VERSION 5.8 ;
BUSBITCHARS "[]" ;
DIVIDERCHAR "/" ;
UNITS
 DATABASE MICRONS 1000 ;
END UNITS
MANUFACTURINGGRID 0.001 ;
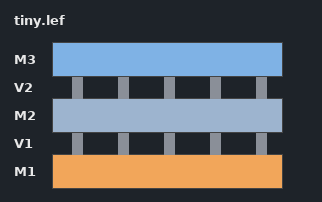
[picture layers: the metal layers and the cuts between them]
LAYER M1
 TYPE ROUTING ; DIRECTION HORIZONTAL ; PITCH 1.0 ; WIDTH 0.2 ; SPACING 0.2 ;
END M1
LAYER V1
 TYPE CUT ; SPACING 0.2 ;
END V1
LAYER M2
 TYPE ROUTING ; DIRECTION VERTICAL ; PITCH 1.0 ; WIDTH 0.2 ; SPACING 0.2 ;
END M2
LAYER V2
 TYPE CUT ; SPACING 0.2 ;
END V2
LAYER M3
 TYPE ROUTING ; DIRECTION HORIZONTAL ; PITCH 1.0 ; WIDTH 0.2 ; SPACING 0.2 ;
END M3
VIA VIA12 DEFAULT
 LAYER M1 ; RECT -0.1 -0.1 0.1 0.1 ;
 LAYER V1 ; RECT -0.05 -0.05 0.05 0.05 ;
 LAYER M2 ; RECT -0.1 -0.1 0.1 0.1 ;
END VIA12
VIA VIA23 DEFAULT
 LAYER M2 ; RECT -0.1 -0.1 0.1 0.1 ;
 LAYER V2 ; RECT -0.05 -0.05 0.05 0.05 ;
 LAYER M3 ; RECT -0.1 -0.1 0.1 0.1 ;
END VIA23
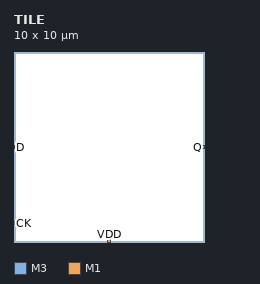
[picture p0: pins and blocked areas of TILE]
MACRO TILE
 CLASS BLOCK ; ORIGIN 0 0 ; SIZE 10 BY 10 ; SYMMETRY X Y ;
 PIN CK
  DIRECTION INPUT ; USE CLOCK ; PORT LAYER M3 ; RECT 0 0.9 0.2 1.1 ; END
 END CK
 PIN D
  DIRECTION INPUT ; USE SIGNAL ; PORT LAYER M3 ; RECT 0 4.9 0.2 5.1 ; END
 END D
 PIN Q
  DIRECTION OUTPUT ; USE SIGNAL ; PORT LAYER M3 ; RECT 9.8 4.9 10 5.1 ; END
 END Q
 PIN VDD
  DIRECTION INOUT ; USE POWER ; PORT LAYER M1 ; RECT 4.9 0 5.1 0.2 ; END
 END VDD
END TILE
END LIBRARY
